VERSION 5.8 ;
BUSBITCHARS "[]" ;
DIVIDERCHAR "/" ;
UNITS
    DATABASE MICRONS 1000 ;
END UNITS

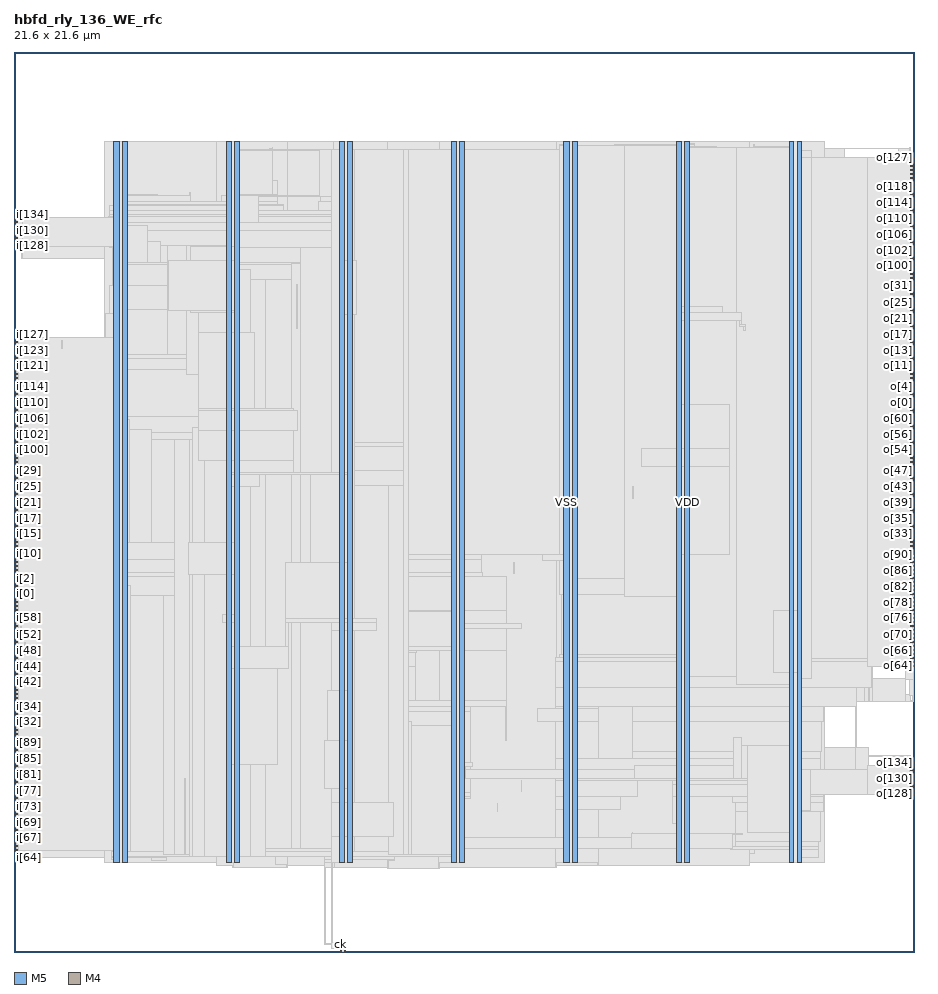
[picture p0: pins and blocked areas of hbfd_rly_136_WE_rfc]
MACRO hbfd_rly_136_WE_rfc
  FOREIGN hbfd_rly_136_WE_rfc 0 0 ;
  CLASS BLOCK ;
  SIZE 21.6 BY 21.6 ;
  PIN ck
    DIRECTION INPUT ;
    USE SIGNAL ;
    PORT
      LAYER M5 ;
        RECT  7.824 0 7.848 0.084 ;
    END
  END ck
  PIN i[0]
    DIRECTION INPUT ;
    USE SIGNAL ;
    PORT
      LAYER M4 ;
        RECT  0 8.592 0.084 8.616 ;
    END
  END i[0]
  PIN i[100]
    DIRECTION INPUT ;
    USE SIGNAL ;
    PORT
      LAYER M4 ;
        RECT  0 12.048 0.084 12.072 ;
    END
  END i[100]
  PIN i[101]
    DIRECTION INPUT ;
    USE SIGNAL ;
    PORT
      LAYER M4 ;
        RECT  0 12.144 0.084 12.168 ;
    END
  END i[101]
  PIN i[102]
    DIRECTION INPUT ;
    USE SIGNAL ;
    PORT
      LAYER M4 ;
        RECT  0 12.24 0.084 12.264 ;
    END
  END i[102]
  PIN i[103]
    DIRECTION INPUT ;
    USE SIGNAL ;
    PORT
      LAYER M4 ;
        RECT  0 12.336 0.084 12.36 ;
    END
  END i[103]
  PIN i[104]
    DIRECTION INPUT ;
    USE SIGNAL ;
    PORT
      LAYER M4 ;
        RECT  0 12.432 0.084 12.456 ;
    END
  END i[104]
  PIN i[105]
    DIRECTION INPUT ;
    USE SIGNAL ;
    PORT
      LAYER M4 ;
        RECT  0 12.528 0.084 12.552 ;
    END
  END i[105]
  PIN i[106]
    DIRECTION INPUT ;
    USE SIGNAL ;
    PORT
      LAYER M4 ;
        RECT  0 12.624 0.084 12.648 ;
    END
  END i[106]
  PIN i[107]
    DIRECTION INPUT ;
    USE SIGNAL ;
    PORT
      LAYER M4 ;
        RECT  0 12.72 0.084 12.744 ;
    END
  END i[107]
  PIN i[108]
    DIRECTION INPUT ;
    USE SIGNAL ;
    PORT
      LAYER M4 ;
        RECT  0 12.816 0.084 12.84 ;
    END
  END i[108]
  PIN i[109]
    DIRECTION INPUT ;
    USE SIGNAL ;
    PORT
      LAYER M4 ;
        RECT  0 12.912 0.084 12.936 ;
    END
  END i[109]
  PIN i[10]
    DIRECTION INPUT ;
    USE SIGNAL ;
    PORT
      LAYER M4 ;
        RECT  0 9.552 0.084 9.576 ;
    END
  END i[10]
  PIN i[110]
    DIRECTION INPUT ;
    USE SIGNAL ;
    PORT
      LAYER M4 ;
        RECT  0 13.008 0.084 13.032 ;
    END
  END i[110]
  PIN i[111]
    DIRECTION INPUT ;
    USE SIGNAL ;
    PORT
      LAYER M4 ;
        RECT  0 13.104 0.084 13.128 ;
    END
  END i[111]
  PIN i[112]
    DIRECTION INPUT ;
    USE SIGNAL ;
    PORT
      LAYER M4 ;
        RECT  0 13.2 0.084 13.224 ;
    END
  END i[112]
  PIN i[113]
    DIRECTION INPUT ;
    USE SIGNAL ;
    PORT
      LAYER M4 ;
        RECT  0 13.296 0.084 13.32 ;
    END
  END i[113]
  PIN i[114]
    DIRECTION INPUT ;
    USE SIGNAL ;
    PORT
      LAYER M4 ;
        RECT  0 13.392 0.084 13.416 ;
    END
  END i[114]
  PIN i[115]
    DIRECTION INPUT ;
    USE SIGNAL ;
    PORT
      LAYER M4 ;
        RECT  0 13.488 0.084 13.512 ;
    END
  END i[115]
  PIN i[116]
    DIRECTION INPUT ;
    USE SIGNAL ;
    PORT
      LAYER M4 ;
        RECT  0 13.584 0.084 13.608 ;
    END
  END i[116]
  PIN i[117]
    DIRECTION INPUT ;
    USE SIGNAL ;
    PORT
      LAYER M4 ;
        RECT  0 13.68 0.084 13.704 ;
    END
  END i[117]
  PIN i[118]
    DIRECTION INPUT ;
    USE SIGNAL ;
    PORT
      LAYER M4 ;
        RECT  0 13.776 0.084 13.8 ;
    END
  END i[118]
  PIN i[119]
    DIRECTION INPUT ;
    USE SIGNAL ;
    PORT
      LAYER M4 ;
        RECT  0 13.872 0.084 13.896 ;
    END
  END i[119]
  PIN i[11]
    DIRECTION INPUT ;
    USE SIGNAL ;
    PORT
      LAYER M4 ;
        RECT  0 9.648 0.084 9.672 ;
    END
  END i[11]
  PIN i[120]
    DIRECTION INPUT ;
    USE SIGNAL ;
    PORT
      LAYER M4 ;
        RECT  0 13.968 0.084 13.992 ;
    END
  END i[120]
  PIN i[121]
    DIRECTION INPUT ;
    USE SIGNAL ;
    PORT
      LAYER M4 ;
        RECT  0 14.064 0.084 14.088 ;
    END
  END i[121]
  PIN i[122]
    DIRECTION INPUT ;
    USE SIGNAL ;
    PORT
      LAYER M4 ;
        RECT  0 14.16 0.084 14.184 ;
    END
  END i[122]
  PIN i[123]
    DIRECTION INPUT ;
    USE SIGNAL ;
    PORT
      LAYER M4 ;
        RECT  0 14.256 0.084 14.28 ;
    END
  END i[123]
  PIN i[124]
    DIRECTION INPUT ;
    USE SIGNAL ;
    PORT
      LAYER M4 ;
        RECT  0 14.352 0.084 14.376 ;
    END
  END i[124]
  PIN i[125]
    DIRECTION INPUT ;
    USE SIGNAL ;
    PORT
      LAYER M4 ;
        RECT  0 14.448 0.084 14.472 ;
    END
  END i[125]
  PIN i[126]
    DIRECTION INPUT ;
    USE SIGNAL ;
    PORT
      LAYER M4 ;
        RECT  0 14.544 0.084 14.568 ;
    END
  END i[126]
  PIN i[127]
    DIRECTION INPUT ;
    USE SIGNAL ;
    PORT
      LAYER M4 ;
        RECT  0 14.64 0.084 14.664 ;
    END
  END i[127]
  PIN i[128]
    DIRECTION INPUT ;
    USE SIGNAL ;
    PORT
      LAYER M4 ;
        RECT  0 16.944 0.084 16.968 ;
    END
  END i[128]
  PIN i[129]
    DIRECTION INPUT ;
    USE SIGNAL ;
    PORT
      LAYER M4 ;
        RECT  0 17.04 0.084 17.064 ;
    END
  END i[129]
  PIN i[12]
    DIRECTION INPUT ;
    USE SIGNAL ;
    PORT
      LAYER M4 ;
        RECT  0 9.744 0.084 9.768 ;
    END
  END i[12]
  PIN i[130]
    DIRECTION INPUT ;
    USE SIGNAL ;
    PORT
      LAYER M4 ;
        RECT  0 17.136 0.084 17.16 ;
    END
  END i[130]
  PIN i[131]
    DIRECTION INPUT ;
    USE SIGNAL ;
    PORT
      LAYER M4 ;
        RECT  0 17.232 0.084 17.256 ;
    END
  END i[131]
  PIN i[132]
    DIRECTION INPUT ;
    USE SIGNAL ;
    PORT
      LAYER M4 ;
        RECT  0 17.328 0.084 17.352 ;
    END
  END i[132]
  PIN i[133]
    DIRECTION INPUT ;
    USE SIGNAL ;
    PORT
      LAYER M4 ;
        RECT  0 17.424 0.084 17.448 ;
    END
  END i[133]
  PIN i[134]
    DIRECTION INPUT ;
    USE SIGNAL ;
    PORT
      LAYER M4 ;
        RECT  0 17.52 0.084 17.544 ;
    END
  END i[134]
  PIN i[135]
    DIRECTION INPUT ;
    USE SIGNAL ;
    PORT
      LAYER M4 ;
        RECT  0 17.616 0.084 17.64 ;
    END
  END i[135]
  PIN i[13]
    DIRECTION INPUT ;
    USE SIGNAL ;
    PORT
      LAYER M4 ;
        RECT  0 9.84 0.084 9.864 ;
    END
  END i[13]
  PIN i[14]
    DIRECTION INPUT ;
    USE SIGNAL ;
    PORT
      LAYER M4 ;
        RECT  0 9.936 0.084 9.96 ;
    END
  END i[14]
  PIN i[15]
    DIRECTION INPUT ;
    USE SIGNAL ;
    PORT
      LAYER M4 ;
        RECT  0 10.032 0.084 10.056 ;
    END
  END i[15]
  PIN i[16]
    DIRECTION INPUT ;
    USE SIGNAL ;
    PORT
      LAYER M4 ;
        RECT  0 10.128 0.084 10.152 ;
    END
  END i[16]
  PIN i[17]
    DIRECTION INPUT ;
    USE SIGNAL ;
    PORT
      LAYER M4 ;
        RECT  0 10.224 0.084 10.248 ;
    END
  END i[17]
  PIN i[18]
    DIRECTION INPUT ;
    USE SIGNAL ;
    PORT
      LAYER M4 ;
        RECT  0 10.32 0.084 10.344 ;
    END
  END i[18]
  PIN i[19]
    DIRECTION INPUT ;
    USE SIGNAL ;
    PORT
      LAYER M4 ;
        RECT  0 10.416 0.084 10.44 ;
    END
  END i[19]
  PIN i[1]
    DIRECTION INPUT ;
    USE SIGNAL ;
    PORT
      LAYER M4 ;
        RECT  0 8.688 0.084 8.712 ;
    END
  END i[1]
  PIN i[20]
    DIRECTION INPUT ;
    USE SIGNAL ;
    PORT
      LAYER M4 ;
        RECT  0 10.512 0.084 10.536 ;
    END
  END i[20]
  PIN i[21]
    DIRECTION INPUT ;
    USE SIGNAL ;
    PORT
      LAYER M4 ;
        RECT  0 10.608 0.084 10.632 ;
    END
  END i[21]
  PIN i[22]
    DIRECTION INPUT ;
    USE SIGNAL ;
    PORT
      LAYER M4 ;
        RECT  0 10.704 0.084 10.728 ;
    END
  END i[22]
  PIN i[23]
    DIRECTION INPUT ;
    USE SIGNAL ;
    PORT
      LAYER M4 ;
        RECT  0 10.8 0.084 10.824 ;
    END
  END i[23]
  PIN i[24]
    DIRECTION INPUT ;
    USE SIGNAL ;
    PORT
      LAYER M4 ;
        RECT  0 10.896 0.084 10.92 ;
    END
  END i[24]
  PIN i[25]
    DIRECTION INPUT ;
    USE SIGNAL ;
    PORT
      LAYER M4 ;
        RECT  0 10.992 0.084 11.016 ;
    END
  END i[25]
  PIN i[26]
    DIRECTION INPUT ;
    USE SIGNAL ;
    PORT
      LAYER M4 ;
        RECT  0 11.088 0.084 11.112 ;
    END
  END i[26]
  PIN i[27]
    DIRECTION INPUT ;
    USE SIGNAL ;
    PORT
      LAYER M4 ;
        RECT  0 11.184 0.084 11.208 ;
    END
  END i[27]
  PIN i[28]
    DIRECTION INPUT ;
    USE SIGNAL ;
    PORT
      LAYER M4 ;
        RECT  0 11.28 0.084 11.304 ;
    END
  END i[28]
  PIN i[29]
    DIRECTION INPUT ;
    USE SIGNAL ;
    PORT
      LAYER M4 ;
        RECT  0 11.376 0.084 11.4 ;
    END
  END i[29]
  PIN i[2]
    DIRECTION INPUT ;
    USE SIGNAL ;
    PORT
      LAYER M4 ;
        RECT  0 8.784 0.084 8.808 ;
    END
  END i[2]
  PIN i[30]
    DIRECTION INPUT ;
    USE SIGNAL ;
    PORT
      LAYER M4 ;
        RECT  0 11.472 0.084 11.496 ;
    END
  END i[30]
  PIN i[31]
    DIRECTION INPUT ;
    USE SIGNAL ;
    PORT
      LAYER M4 ;
        RECT  0 11.568 0.084 11.592 ;
    END
  END i[31]
  PIN i[32]
    DIRECTION INPUT ;
    USE SIGNAL ;
    PORT
      LAYER M4 ;
        RECT  0 5.52 0.084 5.544 ;
    END
  END i[32]
  PIN i[33]
    DIRECTION INPUT ;
    USE SIGNAL ;
    PORT
      LAYER M4 ;
        RECT  0 5.616 0.084 5.64 ;
    END
  END i[33]
  PIN i[34]
    DIRECTION INPUT ;
    USE SIGNAL ;
    PORT
      LAYER M4 ;
        RECT  0 5.712 0.084 5.736 ;
    END
  END i[34]
  PIN i[35]
    DIRECTION INPUT ;
    USE SIGNAL ;
    PORT
      LAYER M4 ;
        RECT  0 5.808 0.084 5.832 ;
    END
  END i[35]
  PIN i[36]
    DIRECTION INPUT ;
    USE SIGNAL ;
    PORT
      LAYER M4 ;
        RECT  0 5.904 0.084 5.928 ;
    END
  END i[36]
  PIN i[37]
    DIRECTION INPUT ;
    USE SIGNAL ;
    PORT
      LAYER M4 ;
        RECT  0 6 0.084 6.024 ;
    END
  END i[37]
  PIN i[38]
    DIRECTION INPUT ;
    USE SIGNAL ;
    PORT
      LAYER M4 ;
        RECT  0 6.096 0.084 6.12 ;
    END
  END i[38]
  PIN i[39]
    DIRECTION INPUT ;
    USE SIGNAL ;
    PORT
      LAYER M4 ;
        RECT  0 6.192 0.084 6.216 ;
    END
  END i[39]
  PIN i[3]
    DIRECTION INPUT ;
    USE SIGNAL ;
    PORT
      LAYER M4 ;
        RECT  0 8.88 0.084 8.904 ;
    END
  END i[3]
  PIN i[40]
    DIRECTION INPUT ;
    USE SIGNAL ;
    PORT
      LAYER M4 ;
        RECT  0 6.288 0.084 6.312 ;
    END
  END i[40]
  PIN i[41]
    DIRECTION INPUT ;
    USE SIGNAL ;
    PORT
      LAYER M4 ;
        RECT  0 6.384 0.084 6.408 ;
    END
  END i[41]
  PIN i[42]
    DIRECTION INPUT ;
    USE SIGNAL ;
    PORT
      LAYER M4 ;
        RECT  0 6.48 0.084 6.504 ;
    END
  END i[42]
  PIN i[43]
    DIRECTION INPUT ;
    USE SIGNAL ;
    PORT
      LAYER M4 ;
        RECT  0 6.576 0.084 6.6 ;
    END
  END i[43]
  PIN i[44]
    DIRECTION INPUT ;
    USE SIGNAL ;
    PORT
      LAYER M4 ;
        RECT  0 6.672 0.084 6.696 ;
    END
  END i[44]
  PIN i[45]
    DIRECTION INPUT ;
    USE SIGNAL ;
    PORT
      LAYER M4 ;
        RECT  0 6.768 0.084 6.792 ;
    END
  END i[45]
  PIN i[46]
    DIRECTION INPUT ;
    USE SIGNAL ;
    PORT
      LAYER M4 ;
        RECT  0 6.864 0.084 6.888 ;
    END
  END i[46]
  PIN i[47]
    DIRECTION INPUT ;
    USE SIGNAL ;
    PORT
      LAYER M4 ;
        RECT  0 6.96 0.084 6.984 ;
    END
  END i[47]
  PIN i[48]
    DIRECTION INPUT ;
    USE SIGNAL ;
    PORT
      LAYER M4 ;
        RECT  0 7.056 0.084 7.08 ;
    END
  END i[48]
  PIN i[49]
    DIRECTION INPUT ;
    USE SIGNAL ;
    PORT
      LAYER M4 ;
        RECT  0 7.152 0.084 7.176 ;
    END
  END i[49]
  PIN i[4]
    DIRECTION INPUT ;
    USE SIGNAL ;
    PORT
      LAYER M4 ;
        RECT  0 8.976 0.084 9 ;
    END
  END i[4]
  PIN i[50]
    DIRECTION INPUT ;
    USE SIGNAL ;
    PORT
      LAYER M4 ;
        RECT  0 7.248 0.084 7.272 ;
    END
  END i[50]
  PIN i[51]
    DIRECTION INPUT ;
    USE SIGNAL ;
    PORT
      LAYER M4 ;
        RECT  0 7.344 0.084 7.368 ;
    END
  END i[51]
  PIN i[52]
    DIRECTION INPUT ;
    USE SIGNAL ;
    PORT
      LAYER M4 ;
        RECT  0 7.44 0.084 7.464 ;
    END
  END i[52]
  PIN i[53]
    DIRECTION INPUT ;
    USE SIGNAL ;
    PORT
      LAYER M4 ;
        RECT  0 7.536 0.084 7.56 ;
    END
  END i[53]
  PIN i[54]
    DIRECTION INPUT ;
    USE SIGNAL ;
    PORT
      LAYER M4 ;
        RECT  0 7.632 0.084 7.656 ;
    END
  END i[54]
  PIN i[55]
    DIRECTION INPUT ;
    USE SIGNAL ;
    PORT
      LAYER M4 ;
        RECT  0 7.728 0.084 7.752 ;
    END
  END i[55]
  PIN i[56]
    DIRECTION INPUT ;
    USE SIGNAL ;
    PORT
      LAYER M4 ;
        RECT  0 7.824 0.084 7.848 ;
    END
  END i[56]
  PIN i[57]
    DIRECTION INPUT ;
    USE SIGNAL ;
    PORT
      LAYER M4 ;
        RECT  0 7.92 0.084 7.944 ;
    END
  END i[57]
  PIN i[58]
    DIRECTION INPUT ;
    USE SIGNAL ;
    PORT
      LAYER M4 ;
        RECT  0 8.016 0.084 8.04 ;
    END
  END i[58]
  PIN i[59]
    DIRECTION INPUT ;
    USE SIGNAL ;
    PORT
      LAYER M4 ;
        RECT  0 8.112 0.084 8.136 ;
    END
  END i[59]
  PIN i[5]
    DIRECTION INPUT ;
    USE SIGNAL ;
    PORT
      LAYER M4 ;
        RECT  0 9.072 0.084 9.096 ;
    END
  END i[5]
  PIN i[60]
    DIRECTION INPUT ;
    USE SIGNAL ;
    PORT
      LAYER M4 ;
        RECT  0 8.208 0.084 8.232 ;
    END
  END i[60]
  PIN i[61]
    DIRECTION INPUT ;
    USE SIGNAL ;
    PORT
      LAYER M4 ;
        RECT  0 8.304 0.084 8.328 ;
    END
  END i[61]
  PIN i[62]
    DIRECTION INPUT ;
    USE SIGNAL ;
    PORT
      LAYER M4 ;
        RECT  0 8.4 0.084 8.424 ;
    END
  END i[62]
  PIN i[63]
    DIRECTION INPUT ;
    USE SIGNAL ;
    PORT
      LAYER M4 ;
        RECT  0 8.496 0.084 8.52 ;
    END
  END i[63]
  PIN i[64]
    DIRECTION INPUT ;
    USE SIGNAL ;
    PORT
      LAYER M4 ;
        RECT  0 2.448 0.084 2.472 ;
    END
  END i[64]
  PIN i[65]
    DIRECTION INPUT ;
    USE SIGNAL ;
    PORT
      LAYER M4 ;
        RECT  0 2.544 0.084 2.568 ;
    END
  END i[65]
  PIN i[66]
    DIRECTION INPUT ;
    USE SIGNAL ;
    PORT
      LAYER M4 ;
        RECT  0 2.64 0.084 2.664 ;
    END
  END i[66]
  PIN i[67]
    DIRECTION INPUT ;
    USE SIGNAL ;
    PORT
      LAYER M4 ;
        RECT  0 2.736 0.084 2.76 ;
    END
  END i[67]
  PIN i[68]
    DIRECTION INPUT ;
    USE SIGNAL ;
    PORT
      LAYER M4 ;
        RECT  0 2.832 0.084 2.856 ;
    END
  END i[68]
  PIN i[69]
    DIRECTION INPUT ;
    USE SIGNAL ;
    PORT
      LAYER M4 ;
        RECT  0 2.928 0.084 2.952 ;
    END
  END i[69]
  PIN i[6]
    DIRECTION INPUT ;
    USE SIGNAL ;
    PORT
      LAYER M4 ;
        RECT  0 9.168 0.084 9.192 ;
    END
  END i[6]
  PIN i[70]
    DIRECTION INPUT ;
    USE SIGNAL ;
    PORT
      LAYER M4 ;
        RECT  0 3.024 0.084 3.048 ;
    END
  END i[70]
  PIN i[71]
    DIRECTION INPUT ;
    USE SIGNAL ;
    PORT
      LAYER M4 ;
        RECT  0 3.12 0.084 3.144 ;
    END
  END i[71]
  PIN i[72]
    DIRECTION INPUT ;
    USE SIGNAL ;
    PORT
      LAYER M4 ;
        RECT  0 3.216 0.084 3.24 ;
    END
  END i[72]
  PIN i[73]
    DIRECTION INPUT ;
    USE SIGNAL ;
    PORT
      LAYER M4 ;
        RECT  0 3.312 0.084 3.336 ;
    END
  END i[73]
  PIN i[74]
    DIRECTION INPUT ;
    USE SIGNAL ;
    PORT
      LAYER M4 ;
        RECT  0 3.408 0.084 3.432 ;
    END
  END i[74]
  PIN i[75]
    DIRECTION INPUT ;
    USE SIGNAL ;
    PORT
      LAYER M4 ;
        RECT  0 3.504 0.084 3.528 ;
    END
  END i[75]
  PIN i[76]
    DIRECTION INPUT ;
    USE SIGNAL ;
    PORT
      LAYER M4 ;
        RECT  0 3.6 0.084 3.624 ;
    END
  END i[76]
  PIN i[77]
    DIRECTION INPUT ;
    USE SIGNAL ;
    PORT
      LAYER M4 ;
        RECT  0 3.696 0.084 3.72 ;
    END
  END i[77]
  PIN i[78]
    DIRECTION INPUT ;
    USE SIGNAL ;
    PORT
      LAYER M4 ;
        RECT  0 3.792 0.084 3.816 ;
    END
  END i[78]
  PIN i[79]
    DIRECTION INPUT ;
    USE SIGNAL ;
    PORT
      LAYER M4 ;
        RECT  0 3.888 0.084 3.912 ;
    END
  END i[79]
  PIN i[7]
    DIRECTION INPUT ;
    USE SIGNAL ;
    PORT
      LAYER M4 ;
        RECT  0 9.264 0.084 9.288 ;
    END
  END i[7]
  PIN i[80]
    DIRECTION INPUT ;
    USE SIGNAL ;
    PORT
      LAYER M4 ;
        RECT  0 3.984 0.084 4.008 ;
    END
  END i[80]
  PIN i[81]
    DIRECTION INPUT ;
    USE SIGNAL ;
    PORT
      LAYER M4 ;
        RECT  0 4.08 0.084 4.104 ;
    END
  END i[81]
  PIN i[82]
    DIRECTION INPUT ;
    USE SIGNAL ;
    PORT
      LAYER M4 ;
        RECT  0 4.176 0.084 4.2 ;
    END
  END i[82]
  PIN i[83]
    DIRECTION INPUT ;
    USE SIGNAL ;
    PORT
      LAYER M4 ;
        RECT  0 4.272 0.084 4.296 ;
    END
  END i[83]
  PIN i[84]
    DIRECTION INPUT ;
    USE SIGNAL ;
    PORT
      LAYER M4 ;
        RECT  0 4.368 0.084 4.392 ;
    END
  END i[84]
  PIN i[85]
    DIRECTION INPUT ;
    USE SIGNAL ;
    PORT
      LAYER M4 ;
        RECT  0 4.464 0.084 4.488 ;
    END
  END i[85]
  PIN i[86]
    DIRECTION INPUT ;
    USE SIGNAL ;
    PORT
      LAYER M4 ;
        RECT  0 4.56 0.084 4.584 ;
    END
  END i[86]
  PIN i[87]
    DIRECTION INPUT ;
    USE SIGNAL ;
    PORT
      LAYER M4 ;
        RECT  0 4.656 0.084 4.68 ;
    END
  END i[87]
  PIN i[88]
    DIRECTION INPUT ;
    USE SIGNAL ;
    PORT
      LAYER M4 ;
        RECT  0 4.752 0.084 4.776 ;
    END
  END i[88]
  PIN i[89]
    DIRECTION INPUT ;
    USE SIGNAL ;
    PORT
      LAYER M4 ;
        RECT  0 4.848 0.084 4.872 ;
    END
  END i[89]
  PIN i[8]
    DIRECTION INPUT ;
    USE SIGNAL ;
    PORT
      LAYER M4 ;
        RECT  0 9.36 0.084 9.384 ;
    END
  END i[8]
  PIN i[90]
    DIRECTION INPUT ;
    USE SIGNAL ;
    PORT
      LAYER M4 ;
        RECT  0 4.944 0.084 4.968 ;
    END
  END i[90]
  PIN i[91]
    DIRECTION INPUT ;
    USE SIGNAL ;
    PORT
      LAYER M4 ;
        RECT  0 5.04 0.084 5.064 ;
    END
  END i[91]
  PIN i[92]
    DIRECTION INPUT ;
    USE SIGNAL ;
    PORT
      LAYER M4 ;
        RECT  0 5.136 0.084 5.16 ;
    END
  END i[92]
  PIN i[93]
    DIRECTION INPUT ;
    USE SIGNAL ;
    PORT
      LAYER M4 ;
        RECT  0 5.232 0.084 5.256 ;
    END
  END i[93]
  PIN i[94]
    DIRECTION INPUT ;
    USE SIGNAL ;
    PORT
      LAYER M4 ;
        RECT  0 5.328 0.084 5.352 ;
    END
  END i[94]
  PIN i[95]
    DIRECTION INPUT ;
    USE SIGNAL ;
    PORT
      LAYER M4 ;
        RECT  0 5.424 0.084 5.448 ;
    END
  END i[95]
  PIN i[96]
    DIRECTION INPUT ;
    USE SIGNAL ;
    PORT
      LAYER M4 ;
        RECT  0 11.664 0.084 11.688 ;
    END
  END i[96]
  PIN i[97]
    DIRECTION INPUT ;
    USE SIGNAL ;
    PORT
      LAYER M4 ;
        RECT  0 11.76 0.084 11.784 ;
    END
  END i[97]
  PIN i[98]
    DIRECTION INPUT ;
    USE SIGNAL ;
    PORT
      LAYER M4 ;
        RECT  0 11.856 0.084 11.88 ;
    END
  END i[98]
  PIN i[99]
    DIRECTION INPUT ;
    USE SIGNAL ;
    PORT
      LAYER M4 ;
        RECT  0 11.952 0.084 11.976 ;
    END
  END i[99]
  PIN i[9]
    DIRECTION INPUT ;
    USE SIGNAL ;
    PORT
      LAYER M4 ;
        RECT  0 9.456 0.084 9.48 ;
    END
  END i[9]
  PIN o[0]
    DIRECTION OUTPUT ;
    USE SIGNAL ;
    PORT
      LAYER M4 ;
        RECT  21.516 13.008 21.6 13.032 ;
    END
  END o[0]
  PIN o[100]
    DIRECTION OUTPUT ;
    USE SIGNAL ;
    PORT
      LAYER M4 ;
        RECT  21.516 16.464 21.6 16.488 ;
    END
  END o[100]
  PIN o[101]
    DIRECTION OUTPUT ;
    USE SIGNAL ;
    PORT
      LAYER M4 ;
        RECT  21.516 16.56 21.6 16.584 ;
    END
  END o[101]
  PIN o[102]
    DIRECTION OUTPUT ;
    USE SIGNAL ;
    PORT
      LAYER M4 ;
        RECT  21.516 16.656 21.6 16.68 ;
    END
  END o[102]
  PIN o[103]
    DIRECTION OUTPUT ;
    USE SIGNAL ;
    PORT
      LAYER M4 ;
        RECT  21.516 16.752 21.6 16.776 ;
    END
  END o[103]
  PIN o[104]
    DIRECTION OUTPUT ;
    USE SIGNAL ;
    PORT
      LAYER M4 ;
        RECT  21.516 16.848 21.6 16.872 ;
    END
  END o[104]
  PIN o[105]
    DIRECTION OUTPUT ;
    USE SIGNAL ;
    PORT
      LAYER M4 ;
        RECT  21.516 16.944 21.6 16.968 ;
    END
  END o[105]
  PIN o[106]
    DIRECTION OUTPUT ;
    USE SIGNAL ;
    PORT
      LAYER M4 ;
        RECT  21.516 17.04 21.6 17.064 ;
    END
  END o[106]
  PIN o[107]
    DIRECTION OUTPUT ;
    USE SIGNAL ;
    PORT
      LAYER M4 ;
        RECT  21.516 17.136 21.6 17.16 ;
    END
  END o[107]
  PIN o[108]
    DIRECTION OUTPUT ;
    USE SIGNAL ;
    PORT
      LAYER M4 ;
        RECT  21.516 17.232 21.6 17.256 ;
    END
  END o[108]
  PIN o[109]
    DIRECTION OUTPUT ;
    USE SIGNAL ;
    PORT
      LAYER M4 ;
        RECT  21.516 17.328 21.6 17.352 ;
    END
  END o[109]
  PIN o[10]
    DIRECTION OUTPUT ;
    USE SIGNAL ;
    PORT
      LAYER M4 ;
        RECT  21.516 13.968 21.6 13.992 ;
    END
  END o[10]
  PIN o[110]
    DIRECTION OUTPUT ;
    USE SIGNAL ;
    PORT
      LAYER M4 ;
        RECT  21.516 17.424 21.6 17.448 ;
    END
  END o[110]
  PIN o[111]
    DIRECTION OUTPUT ;
    USE SIGNAL ;
    PORT
      LAYER M4 ;
        RECT  21.516 17.52 21.6 17.544 ;
    END
  END o[111]
  PIN o[112]
    DIRECTION OUTPUT ;
    USE SIGNAL ;
    PORT
      LAYER M4 ;
        RECT  21.516 17.616 21.6 17.64 ;
    END
  END o[112]
  PIN o[113]
    DIRECTION OUTPUT ;
    USE SIGNAL ;
    PORT
      LAYER M4 ;
        RECT  21.516 17.712 21.6 17.736 ;
    END
  END o[113]
  PIN o[114]
    DIRECTION OUTPUT ;
    USE SIGNAL ;
    PORT
      LAYER M4 ;
        RECT  21.516 17.808 21.6 17.832 ;
    END
  END o[114]
  PIN o[115]
    DIRECTION OUTPUT ;
    USE SIGNAL ;
    PORT
      LAYER M4 ;
        RECT  21.516 17.904 21.6 17.928 ;
    END
  END o[115]
  PIN o[116]
    DIRECTION OUTPUT ;
    USE SIGNAL ;
    PORT
      LAYER M4 ;
        RECT  21.516 18 21.6 18.024 ;
    END
  END o[116]
  PIN o[117]
    DIRECTION OUTPUT ;
    USE SIGNAL ;
    PORT
      LAYER M4 ;
        RECT  21.516 18.096 21.6 18.12 ;
    END
  END o[117]
  PIN o[118]
    DIRECTION OUTPUT ;
    USE SIGNAL ;
    PORT
      LAYER M4 ;
        RECT  21.516 18.192 21.6 18.216 ;
    END
  END o[118]
  PIN o[119]
    DIRECTION OUTPUT ;
    USE SIGNAL ;
    PORT
      LAYER M4 ;
        RECT  21.516 18.288 21.6 18.312 ;
    END
  END o[119]
  PIN o[11]
    DIRECTION OUTPUT ;
    USE SIGNAL ;
    PORT
      LAYER M4 ;
        RECT  21.516 14.064 21.6 14.088 ;
    END
  END o[11]
  PIN o[120]
    DIRECTION OUTPUT ;
    USE SIGNAL ;
    PORT
      LAYER M4 ;
        RECT  21.516 18.384 21.6 18.408 ;
    END
  END o[120]
  PIN o[121]
    DIRECTION OUTPUT ;
    USE SIGNAL ;
    PORT
      LAYER M4 ;
        RECT  21.516 18.48 21.6 18.504 ;
    END
  END o[121]
  PIN o[122]
    DIRECTION OUTPUT ;
    USE SIGNAL ;
    PORT
      LAYER M4 ;
        RECT  21.516 18.576 21.6 18.6 ;
    END
  END o[122]
  PIN o[123]
    DIRECTION OUTPUT ;
    USE SIGNAL ;
    PORT
      LAYER M4 ;
        RECT  21.516 18.672 21.6 18.696 ;
    END
  END o[123]
  PIN o[124]
    DIRECTION OUTPUT ;
    USE SIGNAL ;
    PORT
      LAYER M4 ;
        RECT  21.516 18.768 21.6 18.792 ;
    END
  END o[124]
  PIN o[125]
    DIRECTION OUTPUT ;
    USE SIGNAL ;
    PORT
      LAYER M4 ;
        RECT  21.516 18.864 21.6 18.888 ;
    END
  END o[125]
  PIN o[126]
    DIRECTION OUTPUT ;
    USE SIGNAL ;
    PORT
      LAYER M4 ;
        RECT  21.516 18.96 21.6 18.984 ;
    END
  END o[126]
  PIN o[127]
    DIRECTION OUTPUT ;
    USE SIGNAL ;
    PORT
      LAYER M4 ;
        RECT  21.516 19.056 21.6 19.08 ;
    END
  END o[127]
  PIN o[128]
    DIRECTION OUTPUT ;
    USE SIGNAL ;
    PORT
      LAYER M4 ;
        RECT  21.516 3.792 21.6 3.816 ;
    END
  END o[128]
  PIN o[129]
    DIRECTION OUTPUT ;
    USE SIGNAL ;
    PORT
      LAYER M4 ;
        RECT  21.516 3.888 21.6 3.912 ;
    END
  END o[129]
  PIN o[12]
    DIRECTION OUTPUT ;
    USE SIGNAL ;
    PORT
      LAYER M4 ;
        RECT  21.516 14.16 21.6 14.184 ;
    END
  END o[12]
  PIN o[130]
    DIRECTION OUTPUT ;
    USE SIGNAL ;
    PORT
      LAYER M4 ;
        RECT  21.516 3.984 21.6 4.008 ;
    END
  END o[130]
  PIN o[131]
    DIRECTION OUTPUT ;
    USE SIGNAL ;
    PORT
      LAYER M4 ;
        RECT  21.516 4.08 21.6 4.104 ;
    END
  END o[131]
  PIN o[132]
    DIRECTION OUTPUT ;
    USE SIGNAL ;
    PORT
      LAYER M4 ;
        RECT  21.516 4.176 21.6 4.2 ;
    END
  END o[132]
  PIN o[133]
    DIRECTION OUTPUT ;
    USE SIGNAL ;
    PORT
      LAYER M4 ;
        RECT  21.516 4.272 21.6 4.296 ;
    END
  END o[133]
  PIN o[134]
    DIRECTION OUTPUT ;
    USE SIGNAL ;
    PORT
      LAYER M4 ;
        RECT  21.516 4.368 21.6 4.392 ;
    END
  END o[134]
  PIN o[135]
    DIRECTION OUTPUT ;
    USE SIGNAL ;
    PORT
      LAYER M4 ;
        RECT  21.516 4.464 21.6 4.488 ;
    END
  END o[135]
  PIN o[13]
    DIRECTION OUTPUT ;
    USE SIGNAL ;
    PORT
      LAYER M4 ;
        RECT  21.516 14.256 21.6 14.28 ;
    END
  END o[13]
  PIN o[14]
    DIRECTION OUTPUT ;
    USE SIGNAL ;
    PORT
      LAYER M4 ;
        RECT  21.516 14.352 21.6 14.376 ;
    END
  END o[14]
  PIN o[15]
    DIRECTION OUTPUT ;
    USE SIGNAL ;
    PORT
      LAYER M4 ;
        RECT  21.516 14.448 21.6 14.472 ;
    END
  END o[15]
  PIN o[16]
    DIRECTION OUTPUT ;
    USE SIGNAL ;
    PORT
      LAYER M4 ;
        RECT  21.516 14.544 21.6 14.568 ;
    END
  END o[16]
  PIN o[17]
    DIRECTION OUTPUT ;
    USE SIGNAL ;
    PORT
      LAYER M4 ;
        RECT  21.516 14.64 21.6 14.664 ;
    END
  END o[17]
  PIN o[18]
    DIRECTION OUTPUT ;
    USE SIGNAL ;
    PORT
      LAYER M4 ;
        RECT  21.516 14.736 21.6 14.76 ;
    END
  END o[18]
  PIN o[19]
    DIRECTION OUTPUT ;
    USE SIGNAL ;
    PORT
      LAYER M4 ;
        RECT  21.516 14.832 21.6 14.856 ;
    END
  END o[19]
  PIN o[1]
    DIRECTION OUTPUT ;
    USE SIGNAL ;
    PORT
      LAYER M4 ;
        RECT  21.516 13.104 21.6 13.128 ;
    END
  END o[1]
  PIN o[20]
    DIRECTION OUTPUT ;
    USE SIGNAL ;
    PORT
      LAYER M4 ;
        RECT  21.516 14.928 21.6 14.952 ;
    END
  END o[20]
  PIN o[21]
    DIRECTION OUTPUT ;
    USE SIGNAL ;
    PORT
      LAYER M4 ;
        RECT  21.516 15.024 21.6 15.048 ;
    END
  END o[21]
  PIN o[22]
    DIRECTION OUTPUT ;
    USE SIGNAL ;
    PORT
      LAYER M4 ;
        RECT  21.516 15.12 21.6 15.144 ;
    END
  END o[22]
  PIN o[23]
    DIRECTION OUTPUT ;
    USE SIGNAL ;
    PORT
      LAYER M4 ;
        RECT  21.516 15.216 21.6 15.24 ;
    END
  END o[23]
  PIN o[24]
    DIRECTION OUTPUT ;
    USE SIGNAL ;
    PORT
      LAYER M4 ;
        RECT  21.516 15.312 21.6 15.336 ;
    END
  END o[24]
  PIN o[25]
    DIRECTION OUTPUT ;
    USE SIGNAL ;
    PORT
      LAYER M4 ;
        RECT  21.516 15.408 21.6 15.432 ;
    END
  END o[25]
  PIN o[26]
    DIRECTION OUTPUT ;
    USE SIGNAL ;
    PORT
      LAYER M4 ;
        RECT  21.516 15.504 21.6 15.528 ;
    END
  END o[26]
  PIN o[27]
    DIRECTION OUTPUT ;
    USE SIGNAL ;
    PORT
      LAYER M4 ;
        RECT  21.516 15.6 21.6 15.624 ;
    END
  END o[27]
  PIN o[28]
    DIRECTION OUTPUT ;
    USE SIGNAL ;
    PORT
      LAYER M4 ;
        RECT  21.516 15.696 21.6 15.72 ;
    END
  END o[28]
  PIN o[29]
    DIRECTION OUTPUT ;
    USE SIGNAL ;
    PORT
      LAYER M4 ;
        RECT  21.516 15.792 21.6 15.816 ;
    END
  END o[29]
  PIN o[2]
    DIRECTION OUTPUT ;
    USE SIGNAL ;
    PORT
      LAYER M4 ;
        RECT  21.516 13.2 21.6 13.224 ;
    END
  END o[2]
  PIN o[30]
    DIRECTION OUTPUT ;
    USE SIGNAL ;
    PORT
      LAYER M4 ;
        RECT  21.516 15.888 21.6 15.912 ;
    END
  END o[30]
  PIN o[31]
    DIRECTION OUTPUT ;
    USE SIGNAL ;
    PORT
      LAYER M4 ;
        RECT  21.516 15.984 21.6 16.008 ;
    END
  END o[31]
  PIN o[32]
    DIRECTION OUTPUT ;
    USE SIGNAL ;
    PORT
      LAYER M4 ;
        RECT  21.516 9.936 21.6 9.96 ;
    END
  END o[32]
  PIN o[33]
    DIRECTION OUTPUT ;
    USE SIGNAL ;
    PORT
      LAYER M4 ;
        RECT  21.516 10.032 21.6 10.056 ;
    END
  END o[33]
  PIN o[34]
    DIRECTION OUTPUT ;
    USE SIGNAL ;
    PORT
      LAYER M4 ;
        RECT  21.516 10.128 21.6 10.152 ;
    END
  END o[34]
  PIN o[35]
    DIRECTION OUTPUT ;
    USE SIGNAL ;
    PORT
      LAYER M4 ;
        RECT  21.516 10.224 21.6 10.248 ;
    END
  END o[35]
  PIN o[36]
    DIRECTION OUTPUT ;
    USE SIGNAL ;
    PORT
      LAYER M4 ;
        RECT  21.516 10.32 21.6 10.344 ;
    END
  END o[36]
  PIN o[37]
    DIRECTION OUTPUT ;
    USE SIGNAL ;
    PORT
      LAYER M4 ;
        RECT  21.516 10.416 21.6 10.44 ;
    END
  END o[37]
  PIN o[38]
    DIRECTION OUTPUT ;
    USE SIGNAL ;
    PORT
      LAYER M4 ;
        RECT  21.516 10.512 21.6 10.536 ;
    END
  END o[38]
  PIN o[39]
    DIRECTION OUTPUT ;
    USE SIGNAL ;
    PORT
      LAYER M4 ;
        RECT  21.516 10.608 21.6 10.632 ;
    END
  END o[39]
  PIN o[3]
    DIRECTION OUTPUT ;
    USE SIGNAL ;
    PORT
      LAYER M4 ;
        RECT  21.516 13.296 21.6 13.32 ;
    END
  END o[3]
  PIN o[40]
    DIRECTION OUTPUT ;
    USE SIGNAL ;
    PORT
      LAYER M4 ;
        RECT  21.516 10.704 21.6 10.728 ;
    END
  END o[40]
  PIN o[41]
    DIRECTION OUTPUT ;
    USE SIGNAL ;
    PORT
      LAYER M4 ;
        RECT  21.516 10.8 21.6 10.824 ;
    END
  END o[41]
  PIN o[42]
    DIRECTION OUTPUT ;
    USE SIGNAL ;
    PORT
      LAYER M4 ;
        RECT  21.516 10.896 21.6 10.92 ;
    END
  END o[42]
  PIN o[43]
    DIRECTION OUTPUT ;
    USE SIGNAL ;
    PORT
      LAYER M4 ;
        RECT  21.516 10.992 21.6 11.016 ;
    END
  END o[43]
  PIN o[44]
    DIRECTION OUTPUT ;
    USE SIGNAL ;
    PORT
      LAYER M4 ;
        RECT  21.516 11.088 21.6 11.112 ;
    END
  END o[44]
  PIN o[45]
    DIRECTION OUTPUT ;
    USE SIGNAL ;
    PORT
      LAYER M4 ;
        RECT  21.516 11.184 21.6 11.208 ;
    END
  END o[45]
  PIN o[46]
    DIRECTION OUTPUT ;
    USE SIGNAL ;
    PORT
      LAYER M4 ;
        RECT  21.516 11.28 21.6 11.304 ;
    END
  END o[46]
  PIN o[47]
    DIRECTION OUTPUT ;
    USE SIGNAL ;
    PORT
      LAYER M4 ;
        RECT  21.516 11.376 21.6 11.4 ;
    END
  END o[47]
  PIN o[48]
    DIRECTION OUTPUT ;
    USE SIGNAL ;
    PORT
      LAYER M4 ;
        RECT  21.516 11.472 21.6 11.496 ;
    END
  END o[48]
  PIN o[49]
    DIRECTION OUTPUT ;
    USE SIGNAL ;
    PORT
      LAYER M4 ;
        RECT  21.516 11.568 21.6 11.592 ;
    END
  END o[49]
  PIN o[4]
    DIRECTION OUTPUT ;
    USE SIGNAL ;
    PORT
      LAYER M4 ;
        RECT  21.516 13.392 21.6 13.416 ;
    END
  END o[4]
  PIN o[50]
    DIRECTION OUTPUT ;
    USE SIGNAL ;
    PORT
      LAYER M4 ;
        RECT  21.516 11.664 21.6 11.688 ;
    END
  END o[50]
  PIN o[51]
    DIRECTION OUTPUT ;
    USE SIGNAL ;
    PORT
      LAYER M4 ;
        RECT  21.516 11.76 21.6 11.784 ;
    END
  END o[51]
  PIN o[52]
    DIRECTION OUTPUT ;
    USE SIGNAL ;
    PORT
      LAYER M4 ;
        RECT  21.516 11.856 21.6 11.88 ;
    END
  END o[52]
  PIN o[53]
    DIRECTION OUTPUT ;
    USE SIGNAL ;
    PORT
      LAYER M4 ;
        RECT  21.516 11.952 21.6 11.976 ;
    END
  END o[53]
  PIN o[54]
    DIRECTION OUTPUT ;
    USE SIGNAL ;
    PORT
      LAYER M4 ;
        RECT  21.516 12.048 21.6 12.072 ;
    END
  END o[54]
  PIN o[55]
    DIRECTION OUTPUT ;
    USE SIGNAL ;
    PORT
      LAYER M4 ;
        RECT  21.516 12.144 21.6 12.168 ;
    END
  END o[55]
  PIN o[56]
    DIRECTION OUTPUT ;
    USE SIGNAL ;
    PORT
      LAYER M4 ;
        RECT  21.516 12.24 21.6 12.264 ;
    END
  END o[56]
  PIN o[57]
    DIRECTION OUTPUT ;
    USE SIGNAL ;
    PORT
      LAYER M4 ;
        RECT  21.516 12.336 21.6 12.36 ;
    END
  END o[57]
  PIN o[58]
    DIRECTION OUTPUT ;
    USE SIGNAL ;
    PORT
      LAYER M4 ;
        RECT  21.516 12.432 21.6 12.456 ;
    END
  END o[58]
  PIN o[59]
    DIRECTION OUTPUT ;
    USE SIGNAL ;
    PORT
      LAYER M4 ;
        RECT  21.516 12.528 21.6 12.552 ;
    END
  END o[59]
  PIN o[5]
    DIRECTION OUTPUT ;
    USE SIGNAL ;
    PORT
      LAYER M4 ;
        RECT  21.516 13.488 21.6 13.512 ;
    END
  END o[5]
  PIN o[60]
    DIRECTION OUTPUT ;
    USE SIGNAL ;
    PORT
      LAYER M4 ;
        RECT  21.516 12.624 21.6 12.648 ;
    END
  END o[60]
  PIN o[61]
    DIRECTION OUTPUT ;
    USE SIGNAL ;
    PORT
      LAYER M4 ;
        RECT  21.516 12.72 21.6 12.744 ;
    END
  END o[61]
  PIN o[62]
    DIRECTION OUTPUT ;
    USE SIGNAL ;
    PORT
      LAYER M4 ;
        RECT  21.516 12.816 21.6 12.84 ;
    END
  END o[62]
  PIN o[63]
    DIRECTION OUTPUT ;
    USE SIGNAL ;
    PORT
      LAYER M4 ;
        RECT  21.516 12.912 21.6 12.936 ;
    END
  END o[63]
  PIN o[64]
    DIRECTION OUTPUT ;
    USE SIGNAL ;
    PORT
      LAYER M4 ;
        RECT  21.516 6.864 21.6 6.888 ;
    END
  END o[64]
  PIN o[65]
    DIRECTION OUTPUT ;
    USE SIGNAL ;
    PORT
      LAYER M4 ;
        RECT  21.516 6.96 21.6 6.984 ;
    END
  END o[65]
  PIN o[66]
    DIRECTION OUTPUT ;
    USE SIGNAL ;
    PORT
      LAYER M4 ;
        RECT  21.516 7.056 21.6 7.08 ;
    END
  END o[66]
  PIN o[67]
    DIRECTION OUTPUT ;
    USE SIGNAL ;
    PORT
      LAYER M4 ;
        RECT  21.516 7.152 21.6 7.176 ;
    END
  END o[67]
  PIN o[68]
    DIRECTION OUTPUT ;
    USE SIGNAL ;
    PORT
      LAYER M4 ;
        RECT  21.516 7.248 21.6 7.272 ;
    END
  END o[68]
  PIN o[69]
    DIRECTION OUTPUT ;
    USE SIGNAL ;
    PORT
      LAYER M4 ;
        RECT  21.516 7.344 21.6 7.368 ;
    END
  END o[69]
  PIN o[6]
    DIRECTION OUTPUT ;
    USE SIGNAL ;
    PORT
      LAYER M4 ;
        RECT  21.516 13.584 21.6 13.608 ;
    END
  END o[6]
  PIN o[70]
    DIRECTION OUTPUT ;
    USE SIGNAL ;
    PORT
      LAYER M4 ;
        RECT  21.516 7.44 21.6 7.464 ;
    END
  END o[70]
  PIN o[71]
    DIRECTION OUTPUT ;
    USE SIGNAL ;
    PORT
      LAYER M4 ;
        RECT  21.516 7.536 21.6 7.56 ;
    END
  END o[71]
  PIN o[72]
    DIRECTION OUTPUT ;
    USE SIGNAL ;
    PORT
      LAYER M4 ;
        RECT  21.516 7.632 21.6 7.656 ;
    END
  END o[72]
  PIN o[73]
    DIRECTION OUTPUT ;
    USE SIGNAL ;
    PORT
      LAYER M4 ;
        RECT  21.516 7.728 21.6 7.752 ;
    END
  END o[73]
  PIN o[74]
    DIRECTION OUTPUT ;
    USE SIGNAL ;
    PORT
      LAYER M4 ;
        RECT  21.516 7.824 21.6 7.848 ;
    END
  END o[74]
  PIN o[75]
    DIRECTION OUTPUT ;
    USE SIGNAL ;
    PORT
      LAYER M4 ;
        RECT  21.516 7.92 21.6 7.944 ;
    END
  END o[75]
  PIN o[76]
    DIRECTION OUTPUT ;
    USE SIGNAL ;
    PORT
      LAYER M4 ;
        RECT  21.516 8.016 21.6 8.04 ;
    END
  END o[76]
  PIN o[77]
    DIRECTION OUTPUT ;
    USE SIGNAL ;
    PORT
      LAYER M4 ;
        RECT  21.516 8.112 21.6 8.136 ;
    END
  END o[77]
  PIN o[78]
    DIRECTION OUTPUT ;
    USE SIGNAL ;
    PORT
      LAYER M4 ;
        RECT  21.516 8.208 21.6 8.232 ;
    END
  END o[78]
  PIN o[79]
    DIRECTION OUTPUT ;
    USE SIGNAL ;
    PORT
      LAYER M4 ;
        RECT  21.516 8.304 21.6 8.328 ;
    END
  END o[79]
  PIN o[7]
    DIRECTION OUTPUT ;
    USE SIGNAL ;
    PORT
      LAYER M4 ;
        RECT  21.516 13.68 21.6 13.704 ;
    END
  END o[7]
  PIN o[80]
    DIRECTION OUTPUT ;
    USE SIGNAL ;
    PORT
      LAYER M4 ;
        RECT  21.516 8.4 21.6 8.424 ;
    END
  END o[80]
  PIN o[81]
    DIRECTION OUTPUT ;
    USE SIGNAL ;
    PORT
      LAYER M4 ;
        RECT  21.516 8.496 21.6 8.52 ;
    END
  END o[81]
  PIN o[82]
    DIRECTION OUTPUT ;
    USE SIGNAL ;
    PORT
      LAYER M4 ;
        RECT  21.516 8.592 21.6 8.616 ;
    END
  END o[82]
  PIN o[83]
    DIRECTION OUTPUT ;
    USE SIGNAL ;
    PORT
      LAYER M4 ;
        RECT  21.516 8.688 21.6 8.712 ;
    END
  END o[83]
  PIN o[84]
    DIRECTION OUTPUT ;
    USE SIGNAL ;
    PORT
      LAYER M4 ;
        RECT  21.516 8.784 21.6 8.808 ;
    END
  END o[84]
  PIN o[85]
    DIRECTION OUTPUT ;
    USE SIGNAL ;
    PORT
      LAYER M4 ;
        RECT  21.516 8.88 21.6 8.904 ;
    END
  END o[85]
  PIN o[86]
    DIRECTION OUTPUT ;
    USE SIGNAL ;
    PORT
      LAYER M4 ;
        RECT  21.516 8.976 21.6 9 ;
    END
  END o[86]
  PIN o[87]
    DIRECTION OUTPUT ;
    USE SIGNAL ;
    PORT
      LAYER M4 ;
        RECT  21.516 9.072 21.6 9.096 ;
    END
  END o[87]
  PIN o[88]
    DIRECTION OUTPUT ;
    USE SIGNAL ;
    PORT
      LAYER M4 ;
        RECT  21.516 9.168 21.6 9.192 ;
    END
  END o[88]
  PIN o[89]
    DIRECTION OUTPUT ;
    USE SIGNAL ;
    PORT
      LAYER M4 ;
        RECT  21.516 9.264 21.6 9.288 ;
    END
  END o[89]
  PIN o[8]
    DIRECTION OUTPUT ;
    USE SIGNAL ;
    PORT
      LAYER M4 ;
        RECT  21.516 13.776 21.6 13.8 ;
    END
  END o[8]
  PIN o[90]
    DIRECTION OUTPUT ;
    USE SIGNAL ;
    PORT
      LAYER M4 ;
        RECT  21.516 9.36 21.6 9.384 ;
    END
  END o[90]
  PIN o[91]
    DIRECTION OUTPUT ;
    USE SIGNAL ;
    PORT
      LAYER M4 ;
        RECT  21.516 9.456 21.6 9.48 ;
    END
  END o[91]
  PIN o[92]
    DIRECTION OUTPUT ;
    USE SIGNAL ;
    PORT
      LAYER M4 ;
        RECT  21.516 9.552 21.6 9.576 ;
    END
  END o[92]
  PIN o[93]
    DIRECTION OUTPUT ;
    USE SIGNAL ;
    PORT
      LAYER M4 ;
        RECT  21.516 9.648 21.6 9.672 ;
    END
  END o[93]
  PIN o[94]
    DIRECTION OUTPUT ;
    USE SIGNAL ;
    PORT
      LAYER M4 ;
        RECT  21.516 9.744 21.6 9.768 ;
    END
  END o[94]
  PIN o[95]
    DIRECTION OUTPUT ;
    USE SIGNAL ;
    PORT
      LAYER M4 ;
        RECT  21.516 9.84 21.6 9.864 ;
    END
  END o[95]
  PIN o[96]
    DIRECTION OUTPUT ;
    USE SIGNAL ;
    PORT
      LAYER M4 ;
        RECT  21.516 16.08 21.6 16.104 ;
    END
  END o[96]
  PIN o[97]
    DIRECTION OUTPUT ;
    USE SIGNAL ;
    PORT
      LAYER M4 ;
        RECT  21.516 16.176 21.6 16.2 ;
    END
  END o[97]
  PIN o[98]
    DIRECTION OUTPUT ;
    USE SIGNAL ;
    PORT
      LAYER M4 ;
        RECT  21.516 16.272 21.6 16.296 ;
    END
  END o[98]
  PIN o[99]
    DIRECTION OUTPUT ;
    USE SIGNAL ;
    PORT
      LAYER M4 ;
        RECT  21.516 16.368 21.6 16.392 ;
    END
  END o[99]
  PIN o[9]
    DIRECTION OUTPUT ;
    USE SIGNAL ;
    PORT
      LAYER M4 ;
        RECT  21.516 13.872 21.6 13.896 ;
    END
  END o[9]
  PIN rfi
    DIRECTION INPUT ;
    USE SIGNAL ;
    PORT
      LAYER M4 ;
        RECT  0 17.712 0.084 17.736 ;
    END
  END rfi
  PIN rfo
    DIRECTION OUTPUT ;
    USE SIGNAL ;
    PORT
      LAYER M4 ;
        RECT  21.516 4.56 21.6 4.584 ;
    END
  END rfo
  PIN rs
    DIRECTION INPUT ;
    USE SIGNAL ;
    PORT
      LAYER M5 ;
        RECT  7.92 0 7.944 0.084 ;
    END
  END rs
  PIN VDD
    DIRECTION INOUT ;
    USE POWER ;
    PORT
      LAYER M5 ;
        RECT  18.792 2.151 18.912 19.449 ;
        RECT  16.092 2.151 16.212 19.449 ;
        RECT  13.392 2.151 13.512 19.449 ;
        RECT  10.692 2.151 10.812 19.449 ;
        RECT  7.992 2.151 8.112 19.449 ;
        RECT  5.292 2.151 5.412 19.449 ;
        RECT  2.592 2.151 2.712 19.449 ;
    END
  END VDD
  PIN VSS
    DIRECTION INOUT ;
    USE GROUND ;
    PORT
      LAYER M5 ;
        RECT  18.6 2.137 18.72 19.463 ;
        RECT  15.9 2.137 16.02 19.463 ;
        RECT  13.2 2.137 13.32 19.463 ;
        RECT  10.5 2.137 10.62 19.463 ;
        RECT  7.8 2.137 7.92 19.463 ;
        RECT  5.1 2.137 5.22 19.463 ;
        RECT  2.4 2.137 2.52 19.463 ;
    END
  END VSS
  OBS
    LAYER RVTN ;
     RECT  2.16 2.16 19.44 2.295 ;
     RECT  2.16 2.565 19.44 2.835 ;
     RECT  2.16 3.105 19.44 3.375 ;
     RECT  2.16 3.645 19.44 3.915 ;
     RECT  2.16 4.185 19.44 4.455 ;
     RECT  2.16 4.725 19.44 4.995 ;
     RECT  2.16 5.265 19.44 5.535 ;
     RECT  2.16 5.805 19.44 6.075 ;
     RECT  2.16 6.345 19.44 6.615 ;
     RECT  2.16 6.885 19.44 7.155 ;
     RECT  2.16 7.425 19.44 7.695 ;
     RECT  2.16 7.965 19.44 8.235 ;
     RECT  2.16 8.505 19.44 8.775 ;
     RECT  2.16 9.045 19.44 9.315 ;
     RECT  2.16 9.585 19.44 9.855 ;
     RECT  2.16 10.125 19.44 10.395 ;
     RECT  2.16 10.665 19.44 10.935 ;
     RECT  2.16 11.205 19.44 11.475 ;
     RECT  2.16 11.745 19.44 12.015 ;
     RECT  2.16 12.285 19.44 12.555 ;
     RECT  2.16 12.825 19.44 13.095 ;
     RECT  2.16 13.365 19.44 13.635 ;
     RECT  2.16 13.905 19.44 14.175 ;
     RECT  2.16 14.445 19.44 14.715 ;
     RECT  2.16 14.985 19.44 15.255 ;
     RECT  2.16 15.525 19.44 15.795 ;
     RECT  2.16 16.065 19.44 16.335 ;
     RECT  2.16 16.605 19.44 16.875 ;
     RECT  2.16 17.145 19.44 17.415 ;
     RECT  2.16 17.685 19.44 17.955 ;
     RECT  2.16 18.225 19.44 18.495 ;
     RECT  2.16 18.765 19.44 19.035 ;
     RECT  2.16 19.305 19.44 19.44 ;
    LAYER RVTP ;
     RECT  2.16 2.295 19.44 2.565 ;
     RECT  2.16 2.835 19.44 3.105 ;
     RECT  2.16 3.375 19.44 3.645 ;
     RECT  2.16 3.915 19.44 4.185 ;
     RECT  2.16 4.455 19.44 4.725 ;
     RECT  2.16 4.995 19.44 5.265 ;
     RECT  2.16 5.535 19.44 5.805 ;
     RECT  2.16 6.075 19.44 6.345 ;
     RECT  2.16 6.615 19.44 6.885 ;
     RECT  2.16 7.155 19.44 7.425 ;
     RECT  2.16 7.695 19.44 7.965 ;
     RECT  2.16 8.235 19.44 8.505 ;
     RECT  2.16 8.775 19.44 9.045 ;
     RECT  2.16 9.315 19.44 9.585 ;
     RECT  2.16 9.855 19.44 10.125 ;
     RECT  2.16 10.395 19.44 10.665 ;
     RECT  2.16 10.935 19.44 11.205 ;
     RECT  2.16 11.475 19.44 11.745 ;
     RECT  2.16 12.015 19.44 12.285 ;
     RECT  2.16 12.555 19.44 12.825 ;
     RECT  2.16 13.095 19.44 13.365 ;
     RECT  2.16 13.635 19.44 13.905 ;
     RECT  2.16 14.175 19.44 14.445 ;
     RECT  2.16 14.715 19.44 14.985 ;
     RECT  2.16 15.255 19.44 15.525 ;
     RECT  2.16 15.795 19.44 16.065 ;
     RECT  2.16 16.335 19.44 16.605 ;
     RECT  2.16 16.875 19.44 17.145 ;
     RECT  2.16 17.415 19.44 17.685 ;
     RECT  2.16 17.955 19.44 18.225 ;
     RECT  2.16 18.495 19.44 18.765 ;
     RECT  2.16 19.035 19.44 19.305 ;
    LAYER M1 ;
     RECT  2.16 2.151 19.44 19.449 ;
    LAYER M2 ;
     RECT  0.103 17.082 0.139 17.1 ;
     RECT  0.103 2.268 0.175 2.286 ;
     RECT  0.139 16.848 0.175 17.1 ;
     RECT  0.175 2.268 0.211 2.52 ;
     RECT  0.103 3.312 0.211 3.6 ;
     RECT  0.103 4.734 0.535 4.752 ;
     RECT  1.147 14.652 1.291 14.67 ;
     RECT  0.211 2.268 2.16 3.6 ;
     RECT  0.535 4.734 2.16 4.788 ;
     RECT  1.723 9.396 2.16 9.414 ;
     RECT  0.535 11.826 2.16 11.844 ;
     RECT  0.103 12.834 2.16 12.852 ;
     RECT  1.291 14.454 2.16 14.67 ;
     RECT  0.175 16.65 2.16 17.1 ;
     RECT  2.16 2.151 4.855 19.449 ;
     RECT  4.855 2.07 5.251 19.449 ;
     RECT  5.251 2.034 6.575 19.449 ;
     RECT  6.575 2.07 7.663 19.449 ;
     RECT  7.663 2.034 8.959 19.449 ;
     RECT  8.959 1.998 10.211 19.449 ;
     RECT  10.211 2.034 13.019 19.449 ;
     RECT  13.019 2.07 17.663 19.449 ;
     RECT  17.663 2.151 19.44 19.449 ;
     RECT  19.44 5.886 19.679 8.532 ;
     RECT  19.44 17.496 19.931 19.296 ;
     RECT  19.44 9.324 19.967 12.384 ;
     RECT  19.44 16.074 19.967 16.704 ;
     RECT  19.44 13.608 20.003 14.742 ;
     RECT  19.967 9.324 20.039 10.044 ;
     RECT  19.679 6.012 20.407 8.532 ;
     RECT  19.931 17.856 20.471 18.216 ;
     RECT  19.44 3.888 20.507 4.914 ;
     RECT  20.407 6.012 20.507 8.604 ;
     RECT  20.039 9.666 20.507 10.044 ;
     RECT  19.967 11.142 20.507 12.312 ;
     RECT  19.967 16.686 20.507 16.704 ;
     RECT  20.471 17.856 20.507 17.874 ;
     RECT  20.507 6.012 20.543 8.226 ;
     RECT  20.507 11.556 20.579 12.312 ;
     RECT  20.543 6.012 20.615 6.984 ;
     RECT  20.579 11.556 20.615 11.574 ;
     RECT  20.003 13.608 20.615 14.202 ;
     RECT  19.931 19.278 21.235 19.296 ;
     RECT  20.615 14.184 21.335 14.202 ;
     RECT  20.615 6.012 21.407 6.57 ;
     RECT  20.507 9.666 21.415 9.774 ;
     RECT  21.271 14.994 21.415 15.012 ;
     RECT  21.271 15.768 21.415 15.786 ;
     RECT  21.415 9.522 21.479 9.774 ;
     RECT  21.415 14.994 21.479 16.02 ;
     RECT  20.507 4.698 21.515 4.716 ;
     RECT  21.407 6.012 21.515 6.174 ;
     RECT  20.543 7.776 21.515 7.794 ;
     RECT  21.479 9.522 21.515 9.684 ;
     RECT  21.415 11.556 21.515 11.574 ;
     RECT  21.479 15.066 21.515 15.084 ;
     RECT  21.479 16.002 21.515 16.02 ;
     RECT  21.415 17.811 21.515 17.829 ;
     RECT  21.235 18.702 21.515 19.296 ;
     RECT  21.515 6.012 21.587 6.03 ;
     RECT  21.515 9.522 21.587 9.54 ;
    LAYER M3 ;
     RECT  7.452 0.187 7.47 2.029 ;
     RECT  5.256 2.029 5.274 2.065 ;
     RECT  6.552 2.029 6.57 2.101 ;
     RECT  7.452 2.029 7.686 2.143 ;
     RECT  10.188 1.993 10.206 2.143 ;
     RECT  12.996 2.029 13.014 2.143 ;
     RECT  14.004 2.101 14.022 2.143 ;
     RECT  8.964 1.993 8.982 2.191 ;
     RECT  2.415 2.143 2.505 2.227 ;
     RECT  7.452 2.143 7.905 2.227 ;
     RECT  8.964 2.191 9.126 2.227 ;
     RECT  2.34 2.227 2.505 2.263 ;
     RECT  3.312 2.191 3.654 2.263 ;
     RECT  18.615 2.143 18.705 2.263 ;
     RECT  4.86 2.065 5.274 2.293 ;
     RECT  6.264 2.101 6.57 2.293 ;
     RECT  2.34 2.263 3.654 2.296 ;
     RECT  4.86 2.293 6.57 2.296 ;
     RECT  2.34 2.296 6.57 2.299 ;
     RECT  7.452 2.227 9.126 2.299 ;
     RECT  10.188 2.143 10.605 2.299 ;
     RECT  15.915 2.143 16.005 2.371 ;
     RECT  17.64 2.065 17.658 2.371 ;
     RECT  2.34 2.299 10.605 2.413 ;
     RECT  15.915 2.371 16.074 2.413 ;
     RECT  17.64 2.371 17.766 2.461 ;
     RECT  18.615 2.263 19.314 2.461 ;
     RECT  0.108 2.263 0.126 2.497 ;
     RECT  17.208 2.461 19.314 2.525 ;
     RECT  2.34 2.413 10.797 2.632 ;
     RECT  17.316 2.525 19.314 2.641 ;
     RECT  0.108 2.497 0.198 2.731 ;
     RECT  0.108 2.731 0.342 2.861 ;
     RECT  14.832 2.731 14.85 2.861 ;
     RECT  15.915 2.413 16.197 3.073 ;
     RECT  0.108 2.861 0.234 3.245 ;
     RECT  17.316 2.641 19.35 3.379 ;
     RECT  12.996 2.143 14.022 3.415 ;
     RECT  11.592 3.379 11.61 3.569 ;
     RECT  17.316 3.379 19.422 3.577 ;
     RECT  2.304 2.632 10.797 3.685 ;
     RECT  2.304 3.685 10.962 3.721 ;
     RECT  12.996 3.415 14.562 3.721 ;
     RECT  15.804 3.073 16.197 3.721 ;
     RECT  17.244 3.577 19.422 3.721 ;
     RECT  2.268 3.721 10.962 3.821 ;
     RECT  20.484 3.883 20.502 3.955 ;
     RECT  15.804 3.721 19.422 4.013 ;
     RECT  12.168 3.847 12.186 4.109 ;
     RECT  12.996 3.721 14.958 4.117 ;
     RECT  15.804 4.013 19.35 4.117 ;
     RECT  2.304 3.821 10.962 4.459 ;
     RECT  2.304 4.459 10.998 4.559 ;
     RECT  12.996 4.117 19.35 4.649 ;
     RECT  21.492 4.555 21.51 4.721 ;
     RECT  0.108 3.245 0.162 4.765 ;
     RECT  14.832 4.649 19.35 4.801 ;
     RECT  20.196 3.955 20.502 4.919 ;
     RECT  0.108 4.765 0.558 5.165 ;
     RECT  0.144 5.165 0.558 5.501 ;
     RECT  12.996 4.649 14.022 5.539 ;
     RECT  14.832 4.801 19.386 5.539 ;
     RECT  0.216 5.501 0.558 5.597 ;
     RECT  2.304 4.559 10.962 5.773 ;
     RECT  12.564 5.539 14.022 5.837 ;
     RECT  2.268 5.773 10.962 5.881 ;
     RECT  11.808 5.071 11.826 5.881 ;
     RECT  12.996 5.837 14.022 5.881 ;
     RECT  14.832 5.539 19.422 5.881 ;
     RECT  20.196 4.919 20.214 5.881 ;
     RECT  2.268 5.881 11.826 6.035 ;
     RECT  21.564 6.007 21.582 6.151 ;
     RECT  12.996 5.881 20.214 6.349 ;
     RECT  0.54 5.597 0.558 6.413 ;
     RECT  21.492 6.151 21.582 6.547 ;
     RECT  2.268 6.035 9.63 6.845 ;
     RECT  12.996 6.349 20.574 6.961 ;
     RECT  0.432 6.955 0.45 7.051 ;
     RECT  12.996 6.961 20.61 7.079 ;
     RECT  0.36 7.051 0.45 7.133 ;
     RECT  13.104 7.079 20.61 7.151 ;
     RECT  0.36 7.133 0.378 7.181 ;
     RECT  2.304 6.845 9.63 7.195 ;
     RECT  2.304 7.195 9.666 7.231 ;
     RECT  10.515 6.035 11.826 7.231 ;
     RECT  0.324 7.531 0.342 7.661 ;
     RECT  2.304 7.231 11.826 7.771 ;
     RECT  2.304 7.771 12.186 7.889 ;
     RECT  2.304 7.889 11.826 8.203 ;
     RECT  13.14 7.151 20.61 8.581 ;
     RECT  1.728 8.203 11.826 9.005 ;
     RECT  1.728 9.005 11.25 9.113 ;
     RECT  11.988 9.085 12.006 9.347 ;
     RECT  13.104 8.581 20.61 9.391 ;
     RECT  1.728 9.113 11.214 9.419 ;
     RECT  21.384 6.547 21.582 9.545 ;
     RECT  21.384 9.545 21.51 9.677 ;
     RECT  21.456 9.677 21.51 9.689 ;
     RECT  12.672 9.391 20.61 9.773 ;
     RECT  21.456 9.689 21.474 9.779 ;
     RECT  12.672 9.773 20.502 10.061 ;
     RECT  2.196 9.419 11.214 10.355 ;
     RECT  2.268 10.355 11.214 10.597 ;
     RECT  2.268 10.597 11.394 10.637 ;
     RECT  12.672 10.061 20.07 10.769 ;
     RECT  0.108 10.219 0.126 11.083 ;
     RECT  12.888 10.769 20.07 11.137 ;
     RECT  12.888 11.137 20.502 11.237 ;
     RECT  19.908 11.237 20.502 11.551 ;
     RECT  21.42 11.227 21.438 11.551 ;
     RECT  2.268 10.637 11.214 11.563 ;
     RECT  21.42 11.551 21.51 11.579 ;
     RECT  21.492 11.579 21.51 11.597 ;
     RECT  12.888 11.237 19.17 11.641 ;
     RECT  12.672 11.641 19.17 11.749 ;
     RECT  12.564 11.749 19.17 11.785 ;
     RECT  0.108 11.083 0.342 11.821 ;
     RECT  12.492 11.785 19.17 11.983 ;
     RECT  19.908 11.551 20.61 11.983 ;
     RECT  0.108 11.821 0.558 12.139 ;
     RECT  1.764 11.563 11.214 12.139 ;
     RECT  12.492 11.983 20.61 12.173 ;
     RECT  12.492 12.173 19.206 12.209 ;
     RECT  0.108 12.139 11.214 12.479 ;
     RECT  0.108 12.479 11.106 12.845 ;
     RECT  0.108 12.845 0.126 12.857 ;
     RECT  21.42 12.331 21.438 12.941 ;
     RECT  12.492 12.209 19.134 13.099 ;
     RECT  19.944 12.173 20.61 13.099 ;
     RECT  12.492 13.099 20.61 13.195 ;
     RECT  12.492 13.195 21.402 13.325 ;
     RECT  12.492 13.325 20.61 13.631 ;
     RECT  12.492 13.631 20.574 13.639 ;
     RECT  21.384 13.325 21.402 13.963 ;
     RECT  1.152 12.845 11.106 13.981 ;
     RECT  21.384 13.963 21.438 14.179 ;
     RECT  1.152 13.981 11.25 14.243 ;
     RECT  0.144 14.059 0.162 14.443 ;
     RECT  1.152 14.243 11.178 14.549 ;
     RECT  0.144 14.443 0.342 14.573 ;
     RECT  0.144 14.573 0.234 14.635 ;
     RECT  0.108 14.635 0.234 14.669 ;
     RECT  1.152 14.549 1.278 14.669 ;
     RECT  12.168 13.639 20.574 14.669 ;
     RECT  1.152 14.669 1.17 14.675 ;
     RECT  0.108 14.669 0.126 14.765 ;
     RECT  21.312 14.179 21.438 14.827 ;
     RECT  21.276 14.827 21.438 14.923 ;
     RECT  21.276 14.923 21.474 15.019 ;
     RECT  21.276 15.019 21.51 15.089 ;
     RECT  12.168 14.669 19.998 15.211 ;
     RECT  11.952 15.211 19.998 15.245 ;
     RECT  2.196 14.549 11.178 15.323 ;
     RECT  21.276 15.089 21.474 15.403 ;
     RECT  11.952 15.245 19.314 15.629 ;
     RECT  21.168 15.403 21.474 15.821 ;
     RECT  21.204 15.821 21.474 15.917 ;
     RECT  21.312 15.917 21.474 15.979 ;
     RECT  2.304 15.323 11.178 15.989 ;
     RECT  21.312 15.979 21.51 16.025 ;
     RECT  12.168 15.629 19.314 16.069 ;
     RECT  21.312 16.025 21.438 16.493 ;
     RECT  2.376 15.989 11.178 16.501 ;
     RECT  12.168 16.069 19.962 16.501 ;
     RECT  2.376 16.501 19.962 16.555 ;
     RECT  0.18 16.645 0.198 16.843 ;
     RECT  21.312 16.493 21.402 16.877 ;
     RECT  2.376 16.555 20.502 16.915 ;
     RECT  21.384 16.877 21.402 17.069 ;
     RECT  0.144 16.843 0.198 17.077 ;
     RECT  0.108 17.077 0.198 17.165 ;
     RECT  0.144 17.165 0.198 17.261 ;
     RECT  2.304 16.915 20.502 17.323 ;
     RECT  2.268 17.323 20.502 17.501 ;
     RECT  12.924 17.501 20.502 17.549 ;
     RECT  12.924 17.549 19.17 17.609 ;
     RECT  2.268 17.501 11.97 17.645 ;
     RECT  2.304 17.645 11.97 17.693 ;
     RECT  0.18 17.261 0.198 17.741 ;
     RECT  2.304 17.693 8.982 17.789 ;
     RECT  21.42 17.755 21.438 17.8 ;
     RECT  21.42 17.8 21.51 17.837 ;
     RECT  2.304 17.789 6.462 17.915 ;
     RECT  2.415 17.915 6.462 17.951 ;
     RECT  2.415 17.951 6.318 18.023 ;
     RECT  7.308 17.789 8.982 18.023 ;
     RECT  2.415 18.023 4.23 18.149 ;
     RECT  4.968 18.023 6.318 18.149 ;
     RECT  12.96 17.609 19.17 18.149 ;
     RECT  5.112 18.149 6.318 18.173 ;
     RECT  2.415 18.149 3.438 18.185 ;
     RECT  4.212 18.149 4.23 18.221 ;
     RECT  5.112 18.173 5.397 18.221 ;
     RECT  7.344 18.023 8.982 18.221 ;
     RECT  19.944 17.549 20.502 18.283 ;
     RECT  9.792 17.693 11.97 18.419 ;
     RECT  21.42 17.837 21.438 18.427 ;
     RECT  10.515 18.419 11.97 18.509 ;
     RECT  6.192 18.173 6.318 18.527 ;
     RECT  12.96 18.149 19.134 18.535 ;
     RECT  7.344 18.221 8.097 18.557 ;
     RECT  21.348 18.427 21.438 18.667 ;
     RECT  12.348 18.535 19.134 18.689 ;
     RECT  21.24 18.667 21.438 18.697 ;
     RECT  21.24 18.697 21.51 18.725 ;
     RECT  10.515 18.509 11.538 18.797 ;
     RECT  21.348 18.725 21.51 18.797 ;
     RECT  19.908 18.283 20.502 18.869 ;
     RECT  12.492 18.689 19.134 18.959 ;
     RECT  8.964 18.221 8.982 18.989 ;
     RECT  10.515 18.797 11.178 19.037 ;
     RECT  20.484 18.869 20.502 19.037 ;
     RECT  2.415 18.185 2.697 19.187 ;
     RECT  5.115 18.221 5.397 19.187 ;
     RECT  7.815 18.557 8.097 19.187 ;
     RECT  10.515 19.037 10.797 19.187 ;
     RECT  13.104 18.959 19.134 19.229 ;
     RECT  6.192 18.527 6.21 19.237 ;
     RECT  6.12 19.237 6.21 19.277 ;
     RECT  6.192 19.277 6.21 19.301 ;
     RECT  13.104 19.229 16.938 19.301 ;
     RECT  21.492 18.797 21.51 19.301 ;
     RECT  13.104 19.301 16.866 19.325 ;
     RECT  17.748 19.229 18.705 19.325 ;
     RECT  14.4 19.325 16.866 19.337 ;
     RECT  13.104 19.325 13.305 19.373 ;
     RECT  14.4 19.337 16.326 19.373 ;
     RECT  17.748 19.325 17.766 19.373 ;
     RECT  15.915 19.373 16.326 19.409 ;
     RECT  2.415 19.187 2.505 19.457 ;
     RECT  5.115 19.187 5.205 19.457 ;
     RECT  7.815 19.187 7.905 19.457 ;
     RECT  10.515 19.187 10.605 19.457 ;
     RECT  13.215 19.373 13.305 19.457 ;
     RECT  15.915 19.409 16.005 19.457 ;
     RECT  18.615 19.325 18.705 19.457 ;
    LAYER M4 ;
     RECT  0.06 2.448 0.097 14.664 ;
     RECT  0.06 16.944 0.209 17.736 ;
     RECT  0.097 2.448 2.408 14.76 ;
     RECT  0.209 16.944 2.408 17.64 ;
     RECT  2.408 2.148 2.512 19.452 ;
     RECT  2.512 2.418 2.704 19.182 ;
     RECT  2.704 9.84 2.765 12.792 ;
     RECT  2.704 2.418 2.801 8.808 ;
     RECT  2.704 16.56 3.197 17.448 ;
     RECT  2.765 9.84 3.305 12.552 ;
     RECT  3.197 16.56 3.521 17.064 ;
     RECT  2.801 2.418 3.589 8.568 ;
     RECT  2.704 14.352 3.685 15.432 ;
     RECT  3.521 16.56 3.685 16.968 ;
     RECT  3.589 2.352 3.841 8.568 ;
     RECT  3.305 9.84 3.841 12.312 ;
     RECT  3.685 14.352 4.129 16.968 ;
     RECT  3.841 2.352 4.201 12.312 ;
     RECT  4.201 2.304 4.273 12.312 ;
     RECT  4.129 13.872 4.417 16.968 ;
     RECT  4.273 2.304 4.561 12.6 ;
     RECT  4.417 13.584 4.561 16.968 ;
     RECT  4.561 2.304 5.108 16.968 ;
     RECT  5.108 2.148 5.212 19.452 ;
     RECT  5.212 2.304 5.404 19.272 ;
     RECT  5.404 2.304 5.681 16.392 ;
     RECT  5.404 17.52 5.861 18.168 ;
     RECT  5.681 2.304 6.041 16.152 ;
     RECT  6.041 2.496 6.649 16.152 ;
     RECT  6.649 2.496 6.865 16.536 ;
     RECT  5.861 18.144 7.333 18.168 ;
     RECT  5.404 19.248 7.333 19.272 ;
     RECT  7.441 0.192 7.621 0.216 ;
     RECT  6.865 2.496 7.621 16.92 ;
     RECT  7.333 18.144 7.621 19.272 ;
     RECT  7.621 2.496 7.808 19.272 ;
     RECT  7.621 0.096 7.859 0.216 ;
     RECT  7.808 2.148 7.912 19.452 ;
     RECT  7.859 0.192 7.955 0.216 ;
     RECT  7.912 2.418 8.165 19.272 ;
     RECT  8.165 2.418 8.989 11.208 ;
     RECT  8.989 2.352 9.349 11.208 ;
     RECT  8.165 12.24 9.349 19.272 ;
     RECT  9.349 2.352 9.461 19.272 ;
     RECT  9.461 2.352 9.533 5.544 ;
     RECT  9.533 2.352 10.508 5.448 ;
     RECT  9.461 7.344 10.508 8.184 ;
     RECT  9.461 9.552 10.508 19.272 ;
     RECT  10.508 2.148 10.612 19.452 ;
     RECT  10.612 2.418 10.804 19.272 ;
     RECT  10.804 4.176 10.829 4.44 ;
     RECT  10.804 9.552 13.093 19.272 ;
     RECT  10.804 2.496 13.208 2.76 ;
     RECT  10.829 4.176 13.208 4.392 ;
     RECT  13.093 9.552 13.208 19.368 ;
     RECT  13.208 2.148 13.312 19.452 ;
     RECT  13.312 2.418 13.504 19.368 ;
     RECT  13.504 8.976 14.641 19.368 ;
     RECT  13.504 2.496 14.821 2.76 ;
     RECT  13.504 4.176 14.893 4.392 ;
     RECT  14.821 2.496 15.908 2.856 ;
     RECT  14.893 4.176 15.908 4.488 ;
     RECT  14.641 8.544 15.908 19.368 ;
     RECT  15.908 2.148 16.012 19.452 ;
     RECT  16.012 2.418 16.204 19.32 ;
     RECT  16.204 2.496 17.237 2.856 ;
     RECT  16.204 4.176 17.269 4.488 ;
     RECT  16.204 6.624 17.341 19.32 ;
     RECT  17.269 4.176 17.453 5.16 ;
     RECT  17.237 2.832 17.489 2.856 ;
     RECT  17.453 4.176 17.593 4.968 ;
     RECT  17.593 2.88 18.608 4.968 ;
     RECT  17.341 6.432 18.608 19.32 ;
     RECT  18.608 2.148 18.712 19.452 ;
     RECT  18.712 2.418 18.904 19.182 ;
     RECT  18.904 3.408 19.109 4.392 ;
     RECT  18.904 6.576 19.145 19.08 ;
     RECT  19.109 3.792 20.473 4.392 ;
     RECT  19.145 7.056 20.473 19.08 ;
     RECT  20.473 3.792 21.481 4.488 ;
     RECT  21.481 3.792 21.564 4.584 ;
     RECT  20.473 6.864 21.564 19.08 ;
    LAYER M5 ;
     RECT  7.824 0.016 7.944 0.085 ;
     RECT  7.632 0.085 7.944 0.227 ;
     RECT  7.632 0.227 7.656 2.137 ;
     RECT  2.4 2.137 2.52 2.151 ;
     RECT  5.1 2.137 5.22 2.151 ;
     RECT  7.632 2.137 7.92 2.151 ;
     RECT  10.5 2.137 10.62 2.151 ;
     RECT  13.2 2.137 13.32 2.151 ;
     RECT  15.9 2.137 16.02 2.151 ;
     RECT  18.6 2.137 18.72 2.151 ;
     RECT  7.632 2.151 8.112 2.773 ;
     RECT  0.144 2.581 0.168 2.867 ;
     RECT  7.632 2.773 9.096 3.587 ;
     RECT  7.632 3.587 8.112 3.925 ;
     RECT  4.08 2.341 4.104 4.163 ;
     RECT  5.1 2.151 5.412 4.501 ;
     RECT  7.44 3.925 8.112 5.075 ;
     RECT  7.536 5.075 8.112 6.275 ;
     RECT  18.6 2.151 18.912 6.709 ;
     RECT  5.1 4.501 6.312 6.805 ;
     RECT  5.1 6.805 6.6 7.331 ;
     RECT  0.24 7.141 0.264 7.427 ;
     RECT  7.632 6.275 8.112 7.717 ;
     RECT  0.144 7.621 0.168 7.811 ;
     RECT  5.1 7.331 5.412 7.909 ;
     RECT  6.528 7.331 6.6 7.909 ;
     RECT  7.632 7.717 8.712 7.909 ;
     RECT  6.528 7.909 8.712 8.003 ;
     RECT  4.992 7.909 5.412 8.099 ;
     RECT  18.24 6.709 18.912 8.195 ;
     RECT  5.1 8.099 5.412 9.061 ;
     RECT  6.528 8.003 8.112 9.347 ;
     RECT  15.9 2.151 16.212 9.541 ;
     RECT  4.176 9.061 5.412 9.827 ;
     RECT  14.832 10.885 14.856 11.171 ;
     RECT  5.1 9.827 5.412 11.173 ;
     RECT  0.144 11.029 0.168 11.219 ;
     RECT  5.1 11.173 5.88 11.461 ;
     RECT  7.104 9.347 8.112 11.461 ;
     RECT  5.1 11.461 8.112 11.507 ;
     RECT  15.9 9.541 17.16 11.653 ;
     RECT  5.1 11.507 6.696 11.797 ;
     RECT  15.072 11.653 17.16 12.083 ;
     RECT  4.416 11.797 6.696 12.517 ;
     RECT  0.144 12.517 0.168 12.803 ;
     RECT  4.416 12.517 6.792 12.995 ;
     RECT  4.416 12.995 6.696 13.043 ;
     RECT  15.9 12.083 17.16 13.139 ;
     RECT  1.152 14.485 1.176 14.675 ;
     RECT  4.416 13.043 5.784 14.867 ;
     RECT  17.52 14.917 17.544 15.013 ;
     RECT  17.424 15.013 17.544 15.059 ;
     RECT  15.9 13.139 16.212 15.157 ;
     RECT  17.424 15.059 17.448 15.157 ;
     RECT  7.8 11.507 8.112 15.301 ;
     RECT  15.9 15.157 17.448 15.347 ;
     RECT  4.416 14.867 5.412 15.349 ;
     RECT  4.224 15.349 5.412 15.397 ;
     RECT  15.9 15.347 17.016 15.491 ;
     RECT  6.768 14.965 6.792 16.019 ;
     RECT  3.696 15.397 5.412 16.595 ;
     RECT  7.8 15.301 8.232 16.595 ;
     RECT  21.408 16.693 21.432 16.883 ;
     RECT  4.224 16.595 5.412 16.931 ;
     RECT  2.4 2.151 2.712 19.449 ;
     RECT  5.1 16.931 5.412 19.449 ;
     RECT  7.8 16.595 8.112 19.449 ;
     RECT  10.5 2.151 10.812 19.449 ;
     RECT  13.2 2.151 13.512 19.449 ;
     RECT  15.9 15.491 16.212 19.449 ;
     RECT  18.6 8.195 18.912 19.449 ;
     RECT  2.4 19.449 2.52 19.463 ;
     RECT  5.1 19.449 5.22 19.463 ;
     RECT  7.8 19.449 7.92 19.463 ;
     RECT  10.5 19.449 10.62 19.463 ;
     RECT  13.2 19.449 13.32 19.463 ;
     RECT  15.9 19.449 16.02 19.463 ;
     RECT  18.6 19.449 18.72 19.463 ;
  END
END hbfd_rly_136_WE_rfc
END LIBRARY
